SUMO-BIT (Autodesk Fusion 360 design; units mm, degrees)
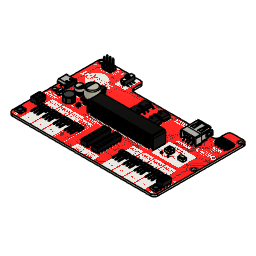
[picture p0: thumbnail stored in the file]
description: model of PinHeader_1x08_P2.54mm_Vertical
part number: PinHeader_1x08_P254mm_Vertical
description: model of PinHeader_1x03_P2.54mm_Vertical
part number: PinHeader_1x03_P254mm_Vertical
description: KiCad electronic assembly
part number: SUMO-BIT 1
description: Part Number
part number: R_0603_1608Metric
part number: (Unsaved)
part number: LED_0603_1608Metric_Blue
base_feature "Base Feature1"
base_feature "Base Feature1"
base_feature "Base Feature1"
base_feature "Base Feature1"
base_feature "Base Feature1"
base_feature "Base Feature1"
base_feature "Base Feature1"
base_feature "Base Feature1"
base_feature "Base Feature1"
base_feature "Base Feature1"
base_feature "Base Feature1"
base_feature "Base Feature1"
base_feature "Base Feature1"
base_feature "Base Feature1"
base_feature "Base Feature1"
base_feature "Base Feature1"
base_feature "Base Feature1"
base_feature "Base Feature1"
base_feature "Base Feature1"
base_feature "Base Feature1"
base_feature "Base Feature1"
base_feature "Base Feature1"
base_feature "Base Feature1"
base_feature "Base Feature1"
base_feature "Base Feature1"
base_feature "Base Feature1"
base_feature "Base Feature1"
base_feature "Base Feature1"
base_feature "Base Feature1"
base_feature "Base Feature1"
base_feature "Base Feature1"
base_feature "Base Feature1"
base_feature "Base Feature1"
base_feature "Base Feature1"
base_feature "Base Feature1"
base_feature "Base Feature1"
base_feature "Base Feature1"
base_feature "Base Feature1"
base_feature "Base Feature1"
base_feature "Base Feature1"
base_feature "Base Feature1"
base_feature "Base Feature1"
base_feature "Base Feature1"
base_feature "Base Feature1"
base_feature "Base Feature1"
base_feature "Base Feature1"
base_feature "Base Feature1"
base_feature "Base Feature1"
base_feature "Base Feature1"
position "Position1"
base_feature "Base Feature1"
base_feature "Base Feature1"
base_feature "Base Feature1"
base_feature "Base Feature1"
base_feature "Base Feature1"
base_feature "Base Feature1"
base_feature "Base Feature1"
base_feature "Base Feature1"
base_feature "Base Feature1"
base_feature "Base Feature1"
base_feature "Base Feature1"
base_feature "Base Feature1"
base_feature "Base Feature1"
base_feature "Base Feature1"
base_feature "Base Feature1"
base_feature "Base Feature1"
base_feature "Base Feature1"
base_feature "Base Feature1"
base_feature "Base Feature1"
base_feature "Base Feature1"
base_feature "Base Feature1"
base_feature "Base Feature1"
base_feature "Base Feature1"
base_feature "Base Feature1"
base_feature "Base Feature1"
base_feature "Base Feature1"
base_feature "Base Feature1"
base_feature "Base Feature1"
base_feature "Base Feature1"
base_feature "Base Feature1"
base_feature "Base Feature1"
base_feature "Base Feature1"
base_feature "Base Feature1"
base_feature "Base Feature1"
base_feature "Base Feature1"
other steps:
create_component "CreateComponent1"
create_component "CreateComponent2"
create_component "CreateComponent3"
create_component "CreateComponent1"
create_component "CreateComponent2"
create_component "CreateComponent3"
create_component "CreateComponent4"
create_component "CreateComponent5"
create_component "CreateComponent6"
create_component "CreateComponent7"
create_component "CreateComponent8"
create_component "CreateComponent9"
create_component "CreateComponent10"
create_component "CreateComponent11"
create_component "CreateComponent12"
create_component "CreateComponent13"
create_component "CreateComponent14"
create_component "CreateComponent15"
create_component "CreateComponent16"
create_component "CreateComponent1"
create_component "CreateComponent17"
create_component "CreateComponent18"
create_component "CreateComponent2"
create_component "CreateComponent1"
create_component "CreateComponent1"
create_component "CreateComponent2"
create_component "CreateComponent3"
create_component "CreateComponent4"
create_component "CreateComponent5"
create_component "CreateComponent6"
create_component "CreateComponent7"
create_component "CreateComponent8"
create_component "CreateComponent9"
create_component "CreateComponent10"
create_component "CreateComponent11"
create_component "CreateComponent12"
create_component "CreateComponent13"
create_component "CreateComponent2"
create_component "CreateComponent3"
create_component "CreateComponent3"
create_component "CreateComponent1"
create_component "CreateComponent1"
create_component "CreateComponent2"
create_component "CreateComponent3"
create_component "CreateComponent4"
create_component "CreateComponent5"
create_component "CreateComponent6"
create_component "CreateComponent7"
create_component "CreateComponent8"
create_component "CreateComponent9"
create_component "CreateComponent10"
create_component "CreateComponent11"
create_component "CreateComponent12"
create_component "CreateComponent13"
create_component "CreateComponent2"
create_component "CreateComponent3"
create_component "CreateComponent4"
create_component "CreateComponent1"
create_component "CreateComponent1"
create_component "CreateComponent2"
create_component "CreateComponent1"
create_component "CreateComponent3"
create_component "CreateComponent1"
create_component "CreateComponent4"
create_component "CreateComponent1"
create_component "CreateComponent5"
create_component "CreateComponent1"
create_component "CreateComponent6"
create_component "CreateComponent1"
create_component "CreateComponent7"
create_component "CreateComponent1"
create_component "CreateComponent8"
create_component "CreateComponent1"
create_component "CreateComponent9"
create_component "CreateComponent1"
create_component "CreateComponent10"
create_component "CreateComponent1"
create_component "CreateComponent11"
create_component "CreateComponent1"
create_component "CreateComponent12"
create_component "CreateComponent1"
create_component "CreateComponent13"
create_component "CreateComponent1"
create_component "CreateComponent14"
create_component "CreateComponent1"
create_component "CreateComponent15"
create_component "CreateComponent1"
create_component "CreateComponent16"
create_component "CreateComponent1"
create_component "CreateComponent17"
create_component "CreateComponent1"
create_component "CreateComponent18"
create_component "CreateComponent1"
create_component "CreateComponent19"
create_component "CreateComponent1"
create_component "CreateComponent20"
create_component "CreateComponent1"
create_component "CreateComponent21"
create_component "CreateComponent1"
create_component "CreateComponent22"
create_component "CreateComponent1"
create_component "CreateComponent23"
create_component "CreateComponent1"
create_component "CreateComponent24"
create_component "CreateComponent1"
create_component "CreateComponent25"
create_component "CreateComponent1"
create_component "CreateComponent26"
create_component "CreateComponent1"
create_component "CreateComponent27"
create_component "CreateComponent1"
create_component "CreateComponent28"
create_component "CreateComponent1"
create_component "CreateComponent29"
create_component "CreateComponent1"
create_component "CreateComponent30"
create_component "CreateComponent1"
create_component "CreateComponent31"
create_component "CreateComponent1"
create_component "CreateComponent32"
create_component "CreateComponent1"
create_component "CreateComponent33"
create_component "CreateComponent1"
create_component "CreateComponent34"
create_component "CreateComponent1"
create_component "CreateComponent35"
create_component "CreateComponent5"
